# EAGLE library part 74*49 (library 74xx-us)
BCD to seven segment DECODER/DRIVER, open collector

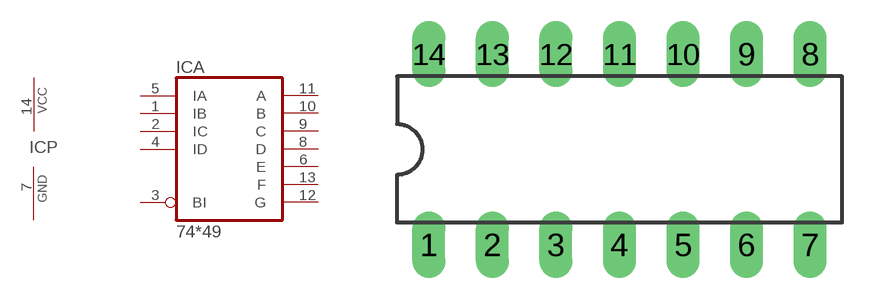
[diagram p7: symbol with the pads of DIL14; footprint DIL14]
Designator prefix IC; gates A=7449 P=PWRN

## 74LS49N  [DIL14]
1  A:IB  in
2  A:IC  in
3  A:BI  in
4  A:ID  in
5  A:IA  in
6  A:E  oc
7  P:GND  pwr
8  A:D  oc
9  A:C  oc
10  A:B  oc
11  A:A  oc
12  A:G  oc
13  A:F  oc
14  P:VCC  pwr

## Footprint DIL14 (pad centres in mm)
Dual In Line Package
drill 0.813 long: 1 -7.62,-3.81; 2 -5.08,-3.81; 3 -2.54,-3.81; 4 0,-3.81; 5 2.54,-3.81; 6 5.08,-3.81; 7 7.62,-3.81; 8 7.62,3.81; 9 5.08,3.81; 10 2.54,3.81; 11 0,3.81; 12 -2.54,3.81; 13 -5.08,3.81; 14 -7.62,3.81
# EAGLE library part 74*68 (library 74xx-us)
Dual 4-bit decade or binary COUNTER

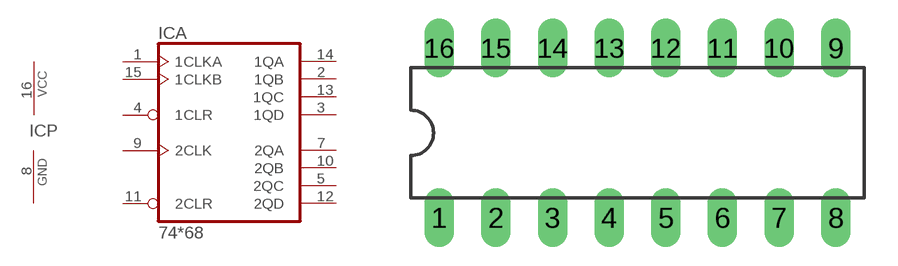
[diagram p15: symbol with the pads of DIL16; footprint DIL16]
Designator prefix IC; gates A=7468 P=PWRN

## 74LS68N  [DIL16]
1  A:1CLKA  in
2  A:1QB  out
3  A:1QD  out
4  A:1CLR  in
5  A:2QC  out
7  A:2QA  out
8  P:GND  pwr
9  A:2CLK  in
10  A:2QB  out
11  A:2CLR  in
12  A:2QD  out
13  A:1QC  out
14  A:1QA  out
15  A:1CLKB  in
16  P:VCC  pwr

## Footprint DIL16 (pad centres in mm)
Dual In Line Package
drill 0.813 long: 1 -8.89,-3.81; 2 -6.35,-3.81; 3 -3.81,-3.81; 4 -1.27,-3.81; 5 1.27,-3.81; 6 3.81,-3.81; 7 6.35,-3.81; 8 8.89,-3.81; 9 8.89,3.81; 10 6.35,3.81; 11 3.81,3.81; 12 1.27,3.81; 13 -1.27,3.81; 14 -3.81,3.81; 15 -6.35,3.81; 16 -8.89,3.81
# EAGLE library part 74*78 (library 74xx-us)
Dual J-K FLIP FLOP, preset, common clock and common clear

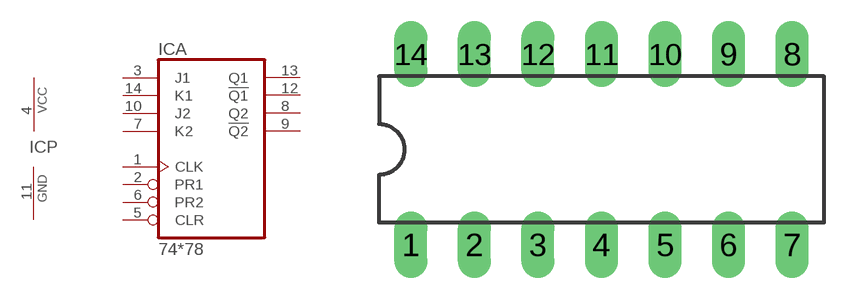
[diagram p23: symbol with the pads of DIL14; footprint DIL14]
Designator prefix IC; gates A=7478 P=PWRN

## 74LS78N  [DIL14]
1  A:CLK  in
2  A:PR1  in
3  A:J1  in
4  P:VCC  pwr
5  A:CLR  in
6  A:PR2  in
7  A:K2  in
8  A:Q2  out
9  A:!Q2  out
10  A:J2  in
11  P:GND  pwr
12  A:!Q1  out
13  A:Q1  out
14  A:K1  in

## Footprint DIL14 (pad centres in mm)
Dual In Line Package
drill 0.813 long: 1 -7.62,-3.81; 2 -5.08,-3.81; 3 -2.54,-3.81; 4 0,-3.81; 5 2.54,-3.81; 6 5.08,-3.81; 7 7.62,-3.81; 8 7.62,3.81; 9 5.08,3.81; 10 2.54,3.81; 11 0,3.81; 12 -2.54,3.81; 13 -5.08,3.81; 14 -7.62,3.81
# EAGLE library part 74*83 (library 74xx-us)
4-bit binary full ADDER, fast carry

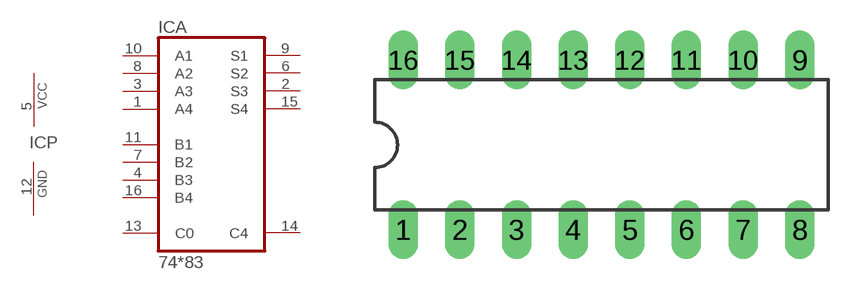
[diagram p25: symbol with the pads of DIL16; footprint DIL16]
Designator prefix IC; gates A=7483 P=PWRN

## 7483N, 74LS83N  [DIL16]
1  A:A4  in
2  A:S3  out
3  A:A3  in
4  A:B3  in
5  P:VCC  pwr
6  A:S2  out
7  A:B2  in
8  A:A2  in
9  A:S1  out
10  A:A1  in
11  A:B1  in
12  P:GND  pwr
13  A:C0  in
14  A:C4  out
15  A:S4  out
16  A:B4  in

## Footprint DIL16 (pad centres in mm)
Dual In Line Package
drill 0.813 long: 1 -8.89,-3.81; 2 -6.35,-3.81; 3 -3.81,-3.81; 4 -1.27,-3.81; 5 1.27,-3.81; 6 3.81,-3.81; 7 6.35,-3.81; 8 8.89,-3.81; 9 8.89,3.81; 10 6.35,3.81; 11 3.81,3.81; 12 1.27,3.81; 13 -1.27,3.81; 14 -3.81,3.81; 15 -6.35,3.81; 16 -8.89,3.81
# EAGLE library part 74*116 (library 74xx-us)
Dual 4-bit LATCH with clear

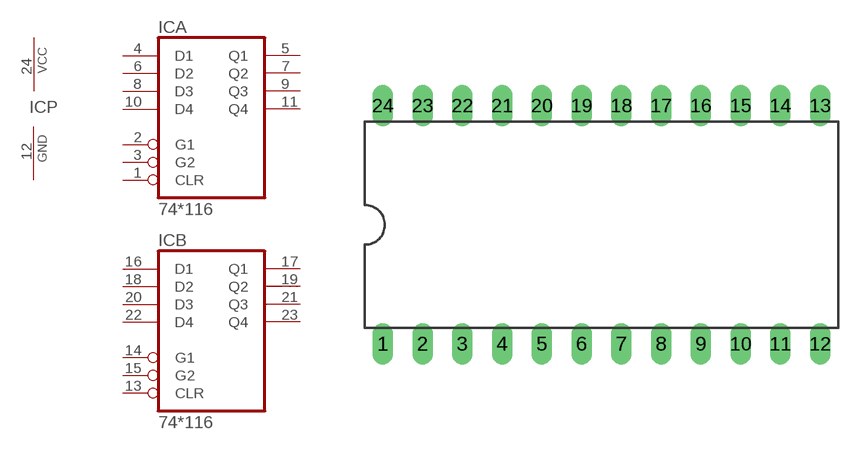
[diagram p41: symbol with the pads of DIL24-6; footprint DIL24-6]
Designator prefix IC; gates A=74116 B=74116 P=PWRN

## 74116N  [DIL24-6]
1  A:CLR  in
2  A:G1  in
3  A:G2  in
4  A:D1  in
5  A:Q1  out
6  A:D2  in
7  A:Q2  out
8  A:D3  in
9  A:Q3  out
10  A:D4  in
11  A:Q4  out
12  P:GND  pwr
13  B:CLR  in
14  B:G1  in
15  B:G2  in
16  B:D1  in
17  B:Q1  out
18  B:D2  in
19  B:Q2  out
20  B:D3  in
21  B:Q3  out
22  B:D4  in
23  B:Q4  out
24  P:VCC  pwr

## Footprint DIL24-6 (pad centres in mm)
Dual In Line Package 0.6 inch
drill 0.813 long: 1 -13.97,-7.62; 2 -11.43,-7.62; 3 -8.89,-7.62; 4 -6.35,-7.62; 5 -3.81,-7.62; 6 -1.27,-7.62; 7 1.27,-7.62; 8 3.81,-7.62; 9 6.35,-7.62; 10 8.89,-7.62; 11 11.43,-7.62; 12 13.97,-7.62; 13 13.97,7.62; 14 11.43,7.62; 15 8.89,7.62; 16 6.35,7.62; 17 3.81,7.62; 18 1.27,7.62; 19 -1.27,7.62; 20 -3.81,7.62; 21 -6.35,7.62; 22 -8.89,7.62; 23 -11.43,7.62; 24 -13.97,7.62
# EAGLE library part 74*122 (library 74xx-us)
Retriggerable monostable MULTIVIBRATOR

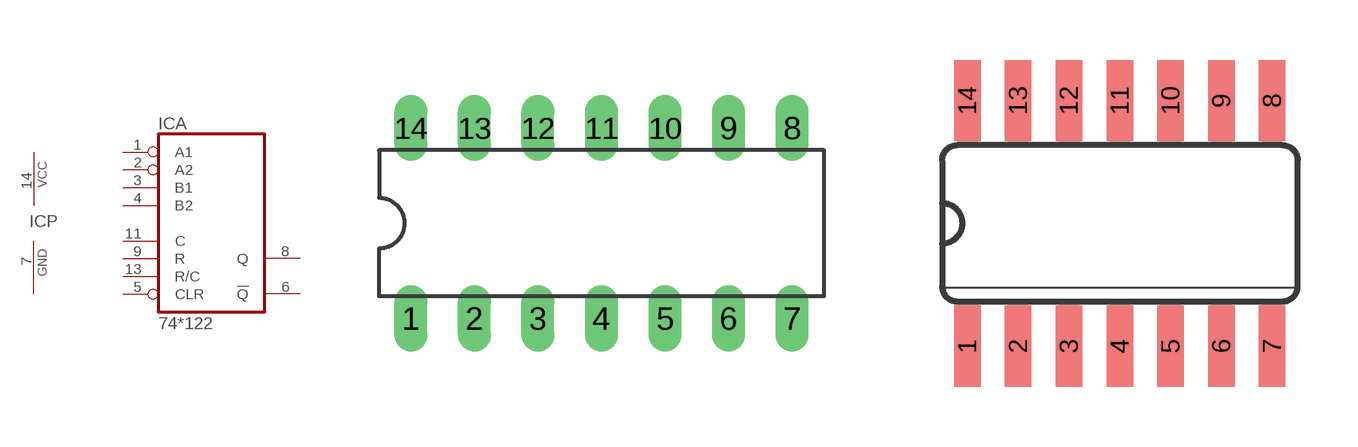
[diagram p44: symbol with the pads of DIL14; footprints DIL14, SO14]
Designator prefix IC; gates A=74122 P=PWRN

## 74LS122N  [DIL14]
1  A:A1  in
2  A:A2  in
3  A:B1  in
4  A:B2  in
5  A:CLR  in
6  A:!Q  out
7  P:GND  pwr
8  A:Q  out
9  A:R  in
11  A:C  in
13  A:R/C  in
14  P:VCC  pwr

## 74LS122D  [SO14]
Pads as for DIL14

## Footprint DIL14 (pad centres in mm)
Dual In Line Package
drill 0.813 long: 1 -7.62,-3.81; 2 -5.08,-3.81; 3 -2.54,-3.81; 4 0,-3.81; 5 2.54,-3.81; 6 5.08,-3.81; 7 7.62,-3.81; 8 7.62,3.81; 9 5.08,3.81; 10 2.54,3.81; 11 0,3.81; 12 -2.54,3.81; 13 -5.08,3.81; 14 -7.62,3.81

## Footprint SO14 (pad centres in mm)
Small Outline package 150 mil
smd 0.66 x 2.032: 1 -3.81,-3.073; 2 -2.54,-3.073; 3 -1.27,-3.073; 4 0,-3.073; 5 1.27,-3.073; 6 2.54,-3.073; 7 3.81,-3.073; 8 3.81,3.073; 9 2.54,3.073; 10 1.27,3.073; 11 0,3.073; 12 -1.27,3.073; 13 -2.54,3.073; 14 -3.81,3.073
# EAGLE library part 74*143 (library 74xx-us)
4-bit COUNTER/LATCH SEVEN-SEGMENT LED/LAMP DRIVER

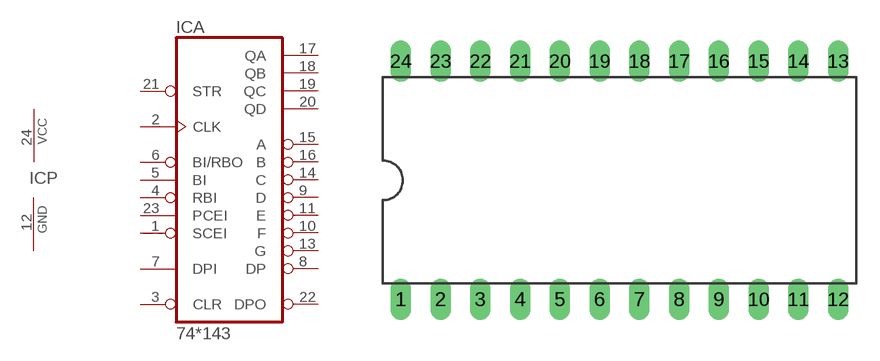
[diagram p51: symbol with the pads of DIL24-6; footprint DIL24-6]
Designator prefix IC; gates A=74143 P=PWRN

## 74143N  [DIL24-6]
1  A:SCEI  in
2  A:CLK  in
3  A:CLR  in
4  A:RBI  in
5  A:BI  in
6  A:BI/RBO
7  A:DPI  in
8  A:DP  oc
9  A:D  oc
10  A:F  oc
11  A:E  oc
12  P:GND  pwr
13  A:G  oc
14  A:C  oc
15  A:A  oc
16  A:B  oc
17  A:QA  out
18  A:QB  out
19  A:QC  out
20  A:QD  out
21  A:STR  in
22  A:DPO  out
23  A:PCEI  in
24  P:VCC  pwr

## Footprint DIL24-6 (pad centres in mm)
Dual In Line Package 0.6 inch
drill 0.813 long: 1 -13.97,-7.62; 2 -11.43,-7.62; 3 -8.89,-7.62; 4 -6.35,-7.62; 5 -3.81,-7.62; 6 -1.27,-7.62; 7 1.27,-7.62; 8 3.81,-7.62; 9 6.35,-7.62; 10 8.89,-7.62; 11 11.43,-7.62; 12 13.97,-7.62; 13 13.97,7.62; 14 11.43,7.62; 15 8.89,7.62; 16 6.35,7.62; 17 3.81,7.62; 18 1.27,7.62; 19 -1.27,7.62; 20 -3.81,7.62; 21 -6.35,7.62; 22 -8.89,7.62; 23 -11.43,7.62; 24 -13.97,7.62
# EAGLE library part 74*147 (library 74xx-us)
10-line to 4-line and 8-line to 3-line PRIORITY DECODER

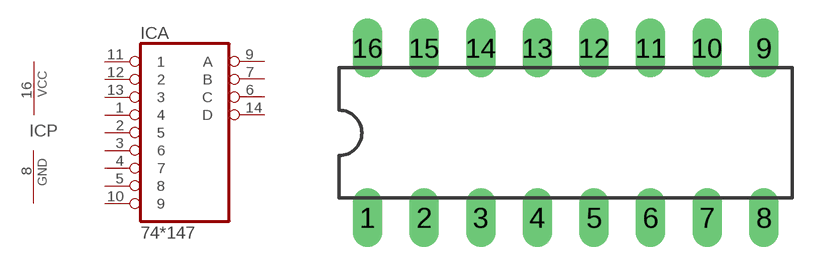
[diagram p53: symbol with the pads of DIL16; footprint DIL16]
Designator prefix IC; gates A=74147 P=PWRN

## 74147N  [DIL16]
1  A:4  in
2  A:5  in
3  A:6  in
4  A:7  in
5  A:8  in
6  A:C  out
7  A:B  out
8  P:GND  pwr
9  A:A  out
10  A:9  in
11  A:1  in
12  A:2  in
13  A:3  in
14  A:D  out
16  P:VCC  pwr

## Footprint DIL16 (pad centres in mm)
Dual In Line Package
drill 0.813 long: 1 -8.89,-3.81; 2 -6.35,-3.81; 3 -3.81,-3.81; 4 -1.27,-3.81; 5 1.27,-3.81; 6 3.81,-3.81; 7 6.35,-3.81; 8 8.89,-3.81; 9 8.89,3.81; 10 6.35,3.81; 11 3.81,3.81; 12 1.27,3.81; 13 -1.27,3.81; 14 -3.81,3.81; 15 -6.35,3.81; 16 -8.89,3.81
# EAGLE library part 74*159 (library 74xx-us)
4-line to 16-line DECODER/DEMULTIPLEXER, open collector

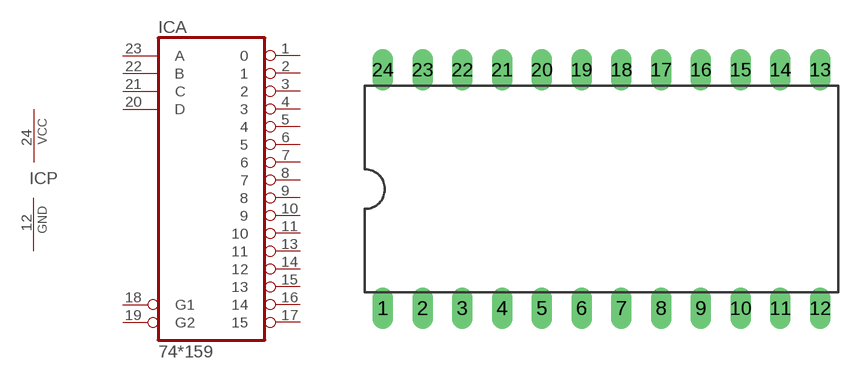
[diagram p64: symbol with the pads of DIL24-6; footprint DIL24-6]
Designator prefix IC; gates A=74159 P=PWRN

## 74159N  [DIL24-6]
1  A:0  oc
2  A:1  oc
3  A:2  oc
4  A:3  oc
5  A:4  oc
6  A:5  oc
7  A:6  oc
8  A:7  oc
9  A:8  oc
10  A:9  oc
11  A:10  oc
12  P:GND  pwr
13  A:11  oc
14  A:12  oc
15  A:13  oc
16  A:14  oc
17  A:15  oc
18  A:G1  in
19  A:G2  in
20  A:D  in
21  A:C  in
22  A:B  in
23  A:A  in
24  P:VCC  pwr

## Footprint DIL24-6 (pad centres in mm)
Dual In Line Package 0.6 inch
drill 0.813 long: 1 -13.97,-7.62; 2 -11.43,-7.62; 3 -8.89,-7.62; 4 -6.35,-7.62; 5 -3.81,-7.62; 6 -1.27,-7.62; 7 1.27,-7.62; 8 3.81,-7.62; 9 6.35,-7.62; 10 8.89,-7.62; 11 11.43,-7.62; 12 13.97,-7.62; 13 13.97,7.62; 14 11.43,7.62; 15 8.89,7.62; 16 6.35,7.62; 17 3.81,7.62; 18 1.27,7.62; 19 -1.27,7.62; 20 -3.81,7.62; 21 -6.35,7.62; 22 -8.89,7.62; 23 -11.43,7.62; 24 -13.97,7.62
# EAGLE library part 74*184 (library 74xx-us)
BCD to binary and binary to BCD CONVERTER

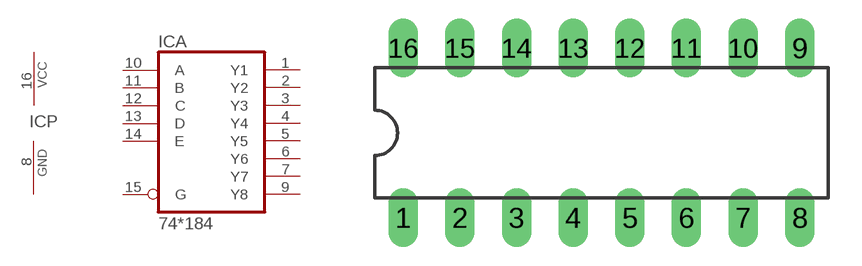
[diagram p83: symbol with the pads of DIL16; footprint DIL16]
Designator prefix IC; gates A=74184 P=PWRN

## 74184N  [DIL16]
1  A:Y1  out
2  A:Y2  out
3  A:Y3  out
4  A:Y4  out
5  A:Y5  out
6  A:Y6  out
7  A:Y7  out
8  P:GND  pwr
9  A:Y8  out
10  A:A  in
11  A:B  in
12  A:C  in
13  A:D  in
14  A:E  in
15  A:G  in
16  P:VCC  pwr

## Footprint DIL16 (pad centres in mm)
Dual In Line Package
drill 0.813 long: 1 -8.89,-3.81; 2 -6.35,-3.81; 3 -3.81,-3.81; 4 -1.27,-3.81; 5 1.27,-3.81; 6 3.81,-3.81; 7 6.35,-3.81; 8 8.89,-3.81; 9 8.89,3.81; 10 6.35,3.81; 11 3.81,3.81; 12 1.27,3.81; 13 -1.27,3.81; 14 -3.81,3.81; 15 -6.35,3.81; 16 -8.89,3.81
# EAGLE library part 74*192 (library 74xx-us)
Synchronous 4-bit UP/DOWN COUNTER

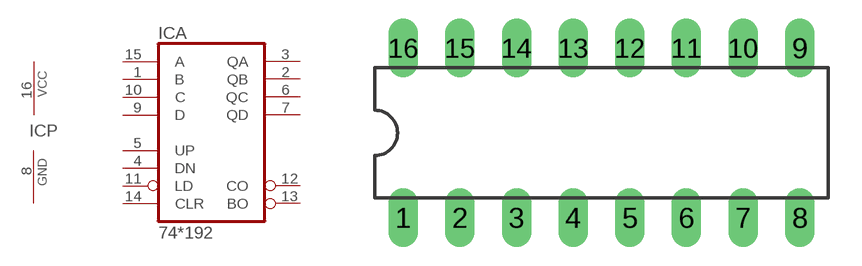
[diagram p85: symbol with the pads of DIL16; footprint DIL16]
Designator prefix IC; gates A=74192 P=PWRN

## 74192N, 74LS192N  [DIL16]
1  A:B  in
2  A:QB  out
3  A:QA  out
4  A:DN  in
5  A:UP  in
6  A:QC  out
7  A:QD  out
8  P:GND  pwr
9  A:D  in
10  A:C  in
11  A:LD  in
12  A:CO  out
13  A:BO  out
14  A:CLR  in
15  A:A  in
16  P:VCC  pwr

## Footprint DIL16 (pad centres in mm)
Dual In Line Package
drill 0.813 long: 1 -8.89,-3.81; 2 -6.35,-3.81; 3 -3.81,-3.81; 4 -1.27,-3.81; 5 1.27,-3.81; 6 3.81,-3.81; 7 6.35,-3.81; 8 8.89,-3.81; 9 8.89,3.81; 10 6.35,3.81; 11 3.81,3.81; 12 1.27,3.81; 13 -1.27,3.81; 14 -3.81,3.81; 15 -6.35,3.81; 16 -8.89,3.81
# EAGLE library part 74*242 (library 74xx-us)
Quadruple BUS TRANSCEIVER

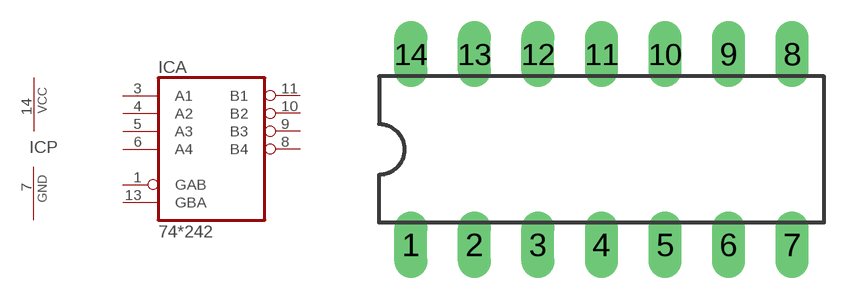
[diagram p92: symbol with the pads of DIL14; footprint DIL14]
Designator prefix IC; gates A=74242 P=PWRN

## 74242N  [DIL14]
1  A:GAB  in
3  A:A1
4  A:A2
5  A:A3
6  A:A4
7  P:GND  pwr
8  A:B4
9  A:B3
10  A:B2
11  A:B1
13  A:GBA  in
14  P:VCC  pwr

## Footprint DIL14 (pad centres in mm)
Dual In Line Package
drill 0.813 long: 1 -7.62,-3.81; 2 -5.08,-3.81; 3 -2.54,-3.81; 4 0,-3.81; 5 2.54,-3.81; 6 5.08,-3.81; 7 7.62,-3.81; 8 7.62,3.81; 9 5.08,3.81; 10 2.54,3.81; 11 0,3.81; 12 -2.54,3.81; 13 -5.08,3.81; 14 -7.62,3.81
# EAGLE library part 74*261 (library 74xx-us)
2 by 4 bit parallel binary MULTIPLEXER

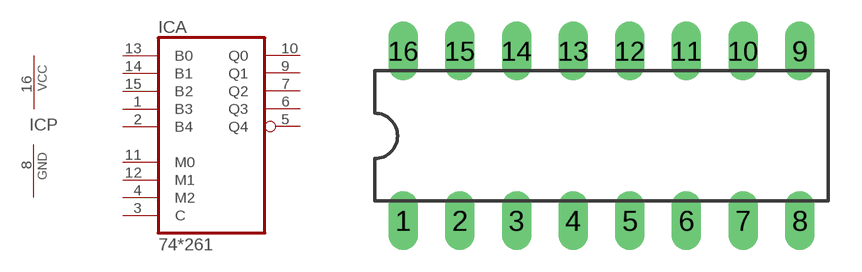
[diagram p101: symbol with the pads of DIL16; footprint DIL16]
Designator prefix IC; gates A=74261 P=PWRN

## 74261N  [DIL16]
1  A:B3  in
2  A:B4  in
3  A:C  in
4  A:M2  in
5  A:Q4  out
6  A:Q3  out
7  A:Q2  out
8  P:GND  pwr
9  A:Q1  out
10  A:Q0  out
11  A:M0  in
12  A:M1  in
13  A:B0  in
14  A:B1  in
15  A:B2  in
16  P:VCC  pwr

## Footprint DIL16 (pad centres in mm)
Dual In Line Package
drill 0.813 long: 1 -8.89,-3.81; 2 -6.35,-3.81; 3 -3.81,-3.81; 4 -1.27,-3.81; 5 1.27,-3.81; 6 3.81,-3.81; 7 6.35,-3.81; 8 8.89,-3.81; 9 8.89,3.81; 10 6.35,3.81; 11 3.81,3.81; 12 1.27,3.81; 13 -1.27,3.81; 14 -3.81,3.81; 15 -6.35,3.81; 16 -8.89,3.81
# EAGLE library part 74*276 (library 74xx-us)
Quadruple J-K FLIP FLOP

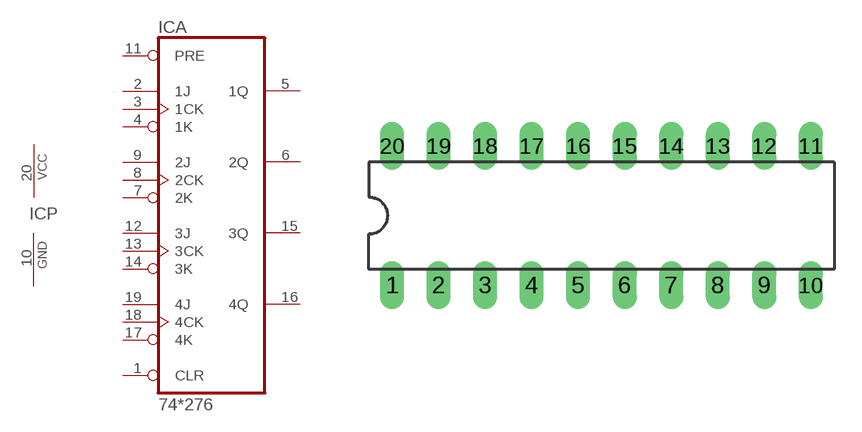
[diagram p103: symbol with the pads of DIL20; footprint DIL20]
Designator prefix IC; gates A=74276 P=PWRN

## 74276N  [DIL20]
1  A:CLR  in
2  A:1J  in
3  A:1CK  in
4  A:1K  in
5  A:1Q  out
6  A:2Q  out
7  A:2K  in
8  A:2CK  in
9  A:2J  in
10  P:GND  pwr
11  A:PRE  in
12  A:3J  in
13  A:3CK  in
14  A:3K  in
15  A:3Q  out
16  A:4Q  out
17  A:4K  in
18  A:4CK  in
19  A:4J  in
20  P:VCC  pwr

## Footprint DIL20 (pad centres in mm)
Dual In Line Package
drill 0.813 long: 1 -11.43,-3.81; 2 -8.89,-3.81; 3 -6.35,-3.81; 4 -3.81,-3.81; 5 -1.27,-3.81; 6 1.27,-3.81; 7 3.81,-3.81; 8 6.35,-3.81; 9 8.89,-3.81; 10 11.43,-3.81; 11 11.43,3.81; 12 8.89,3.81; 13 6.35,3.81; 14 3.81,3.81; 15 1.27,3.81; 16 -1.27,3.81; 17 -3.81,3.81; 18 -6.35,3.81; 19 -8.89,3.81; 20 -11.43,3.81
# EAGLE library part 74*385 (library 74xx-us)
Quadruple serial ADDER/SUBTRACTOR

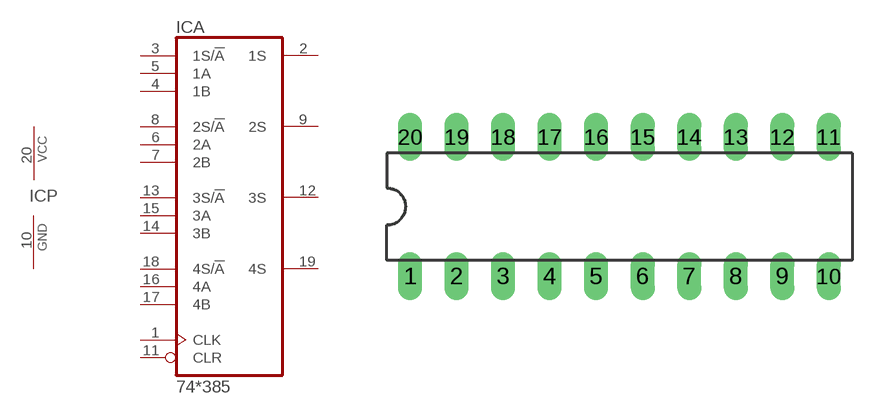
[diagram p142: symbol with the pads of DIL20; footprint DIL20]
Designator prefix IC; gates A=74385 P=PWRN

## 74385N  [DIL20]
1  A:CLK  in
2  A:1S  out
3  A:1S/!A  in
4  A:1B  in
5  A:1A  in
6  A:2A  in
7  A:2B  in
8  A:2S/!A  in
9  A:2S  out
10  P:GND  pwr
11  A:CLR  in
12  A:3S  out
13  A:3S/!A  in
14  A:3B  in
15  A:3A  in
16  A:4A  in
17  A:4B  in
18  A:4S/!A  in
19  A:4S  out
20  P:VCC  pwr

## Footprint DIL20 (pad centres in mm)
Dual In Line Package
drill 0.813 long: 1 -11.43,-3.81; 2 -8.89,-3.81; 3 -6.35,-3.81; 4 -3.81,-3.81; 5 -1.27,-3.81; 6 1.27,-3.81; 7 3.81,-3.81; 8 6.35,-3.81; 9 8.89,-3.81; 10 11.43,-3.81; 11 11.43,3.81; 12 8.89,3.81; 13 6.35,3.81; 14 3.81,3.81; 15 1.27,3.81; 16 -1.27,3.81; 17 -3.81,3.81; 18 -6.35,3.81; 19 -8.89,3.81; 20 -11.43,3.81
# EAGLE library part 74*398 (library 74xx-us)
Quadruple 2-input MULTIPLEXER, storage

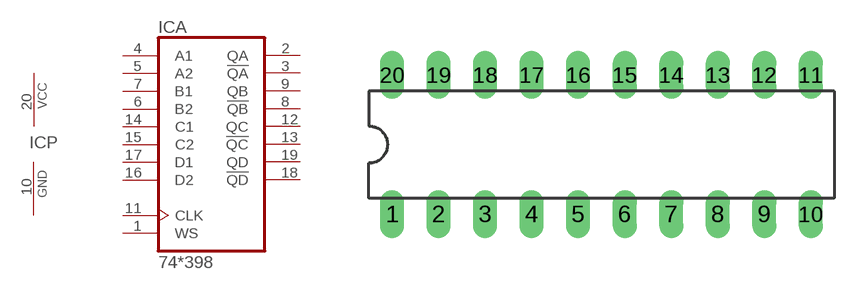
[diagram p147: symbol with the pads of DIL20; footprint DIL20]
Designator prefix IC; gates A=74398 P=PWRN

## 74398N  [DIL20]
1  A:WS  in
2  A:QA  out
3  A:!QA  out
4  A:A1  in
5  A:A2  in
6  A:B2  in
7  A:B1  in
8  A:!QB  out
9  A:QB  out
10  P:GND  pwr
11  A:CLK  in
12  A:QC  out
13  A:!QC  out
14  A:C1  in
15  A:C2  in
16  A:D2  in
17  A:D1  in
18  A:!QD  out
19  A:QD  out
20  P:VCC  pwr

## Footprint DIL20 (pad centres in mm)
Dual In Line Package
drill 0.813 long: 1 -11.43,-3.81; 2 -8.89,-3.81; 3 -6.35,-3.81; 4 -3.81,-3.81; 5 -1.27,-3.81; 6 1.27,-3.81; 7 3.81,-3.81; 8 6.35,-3.81; 9 8.89,-3.81; 10 11.43,-3.81; 11 11.43,3.81; 12 8.89,3.81; 13 6.35,3.81; 14 3.81,3.81; 15 1.27,3.81; 16 -1.27,3.81; 17 -3.81,3.81; 18 -6.35,3.81; 19 -8.89,3.81; 20 -11.43,3.81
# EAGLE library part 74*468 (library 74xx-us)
Inverted octal BUFFER, 3-state

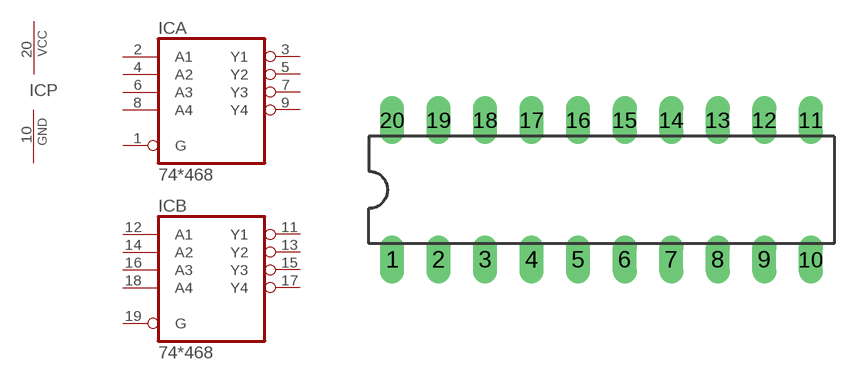
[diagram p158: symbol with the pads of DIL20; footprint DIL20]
Designator prefix IC; gates A=74468 B=74468 P=PWRN

## 74468N  [DIL20]
1  A:G  in
2  A:A1  in
3  A:Y1  hiz
4  A:A2  in
5  A:Y2  hiz
6  A:A3  in
7  A:Y3  hiz
8  A:A4  in
9  A:Y4  hiz
10  P:GND  pwr
11  B:Y1  hiz
12  B:A1  in
13  B:Y2  hiz
14  B:A2  in
15  B:Y3  hiz
16  B:A3  in
17  B:Y4  hiz
18  B:A4  in
19  B:G  in
20  P:VCC  pwr

## Footprint DIL20 (pad centres in mm)
Dual In Line Package
drill 0.813 long: 1 -11.43,-3.81; 2 -8.89,-3.81; 3 -6.35,-3.81; 4 -3.81,-3.81; 5 -1.27,-3.81; 6 1.27,-3.81; 7 3.81,-3.81; 8 6.35,-3.81; 9 8.89,-3.81; 10 11.43,-3.81; 11 11.43,3.81; 12 8.89,3.81; 13 6.35,3.81; 14 3.81,3.81; 15 1.27,3.81; 16 -1.27,3.81; 17 -3.81,3.81; 18 -6.35,3.81; 19 -8.89,3.81; 20 -11.43,3.81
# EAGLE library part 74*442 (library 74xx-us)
4 bit tridirectional BUS DRIVER

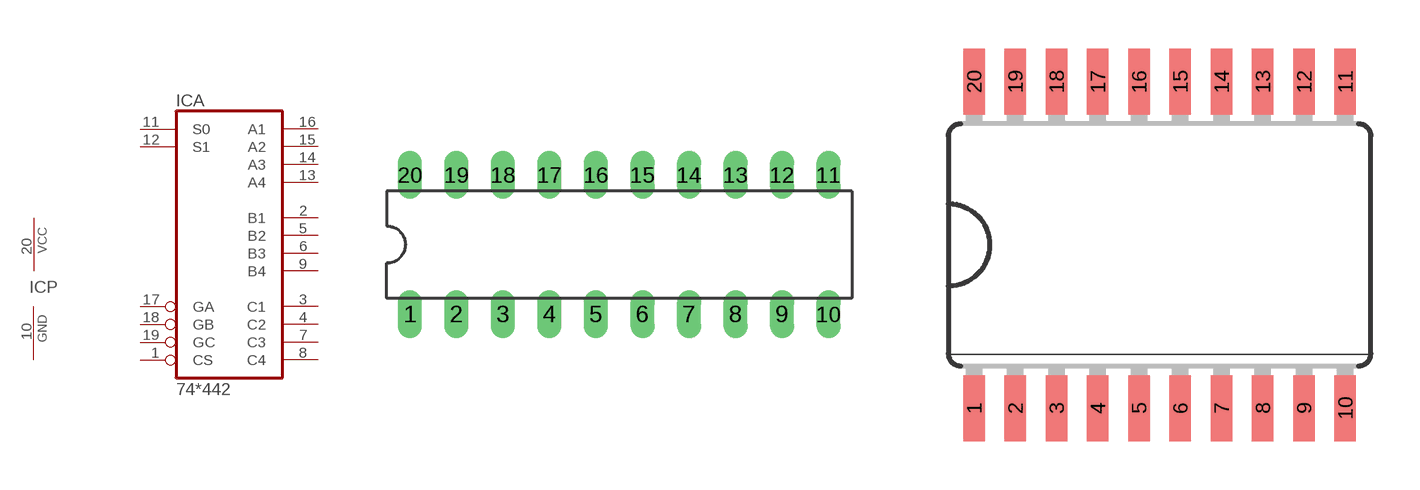
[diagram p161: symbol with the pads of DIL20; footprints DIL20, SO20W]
Designator prefix IC; gates A=74440 P=PWRN

## 74LS442N  [DIL20]
1  A:CS  in
2  A:B1
3  A:C1
4  A:C2
5  A:B2
6  A:B3
7  A:C3
8  A:C4
9  A:B4
10  P:GND  pwr
11  A:S0  in
12  A:S1  in
13  A:A4
14  A:A3
15  A:A2
16  A:A1
17  A:GA  in
18  A:GB  in
19  A:GC  in
20  P:VCC  pwr

## 74LS442J  [SO20W]
Pads as for DIL20

## Footprint DIL20 (pad centres in mm)
Dual In Line Package
drill 0.813 long: 1 -11.43,-3.81; 2 -8.89,-3.81; 3 -6.35,-3.81; 4 -3.81,-3.81; 5 -1.27,-3.81; 6 1.27,-3.81; 7 3.81,-3.81; 8 6.35,-3.81; 9 8.89,-3.81; 10 11.43,-3.81; 11 11.43,3.81; 12 8.89,3.81; 13 6.35,3.81; 14 3.81,3.81; 15 1.27,3.81; 16 -1.27,3.81; 17 -3.81,3.81; 18 -6.35,3.81; 19 -8.89,3.81; 20 -11.43,3.81

## Footprint SO20W (pad centres in mm)
Wide Small Outline package 300 mil
smd 0.66 x 2.032: 1 -5.715,-5.029; 2 -4.445,-5.029; 3 -3.175,-5.029; 4 -1.905,-5.029; 5 -0.635,-5.029; 6 0.635,-5.029; 7 1.905,-5.029; 8 3.175,-5.029; 9 4.445,-5.029; 10 5.715,-5.029; 11 5.715,5.029; 12 4.445,5.029; 13 3.175,5.029; 14 1.905,5.029; 15 0.635,5.029; 16 -0.635,5.029; 17 -1.905,5.029; 18 -3.175,5.029; 19 -4.445,5.029; 20 -5.715,5.029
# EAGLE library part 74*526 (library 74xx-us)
16-bit programmable COMPARATOR

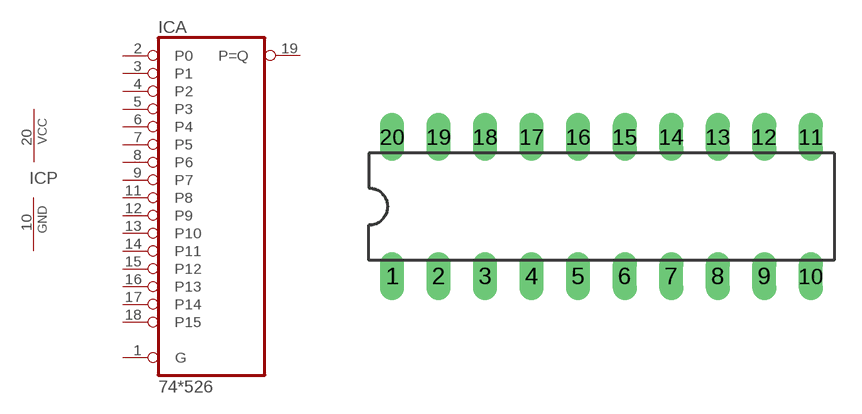
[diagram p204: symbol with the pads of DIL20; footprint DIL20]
Designator prefix IC; gates A=74526 P=PWRN

## 74ALS526N  [DIL20]
1  A:G  in
2  A:P0  in
3  A:P1  in
4  A:P2  in
5  A:P3  in
6  A:P4  in
7  A:P5  in
8  A:P6  in
9  A:P7  in
10  P:GND  pwr
11  A:P8  in
12  A:P9  in
13  A:P10  in
14  A:P11  in
15  A:P12  in
16  A:P13  in
17  A:P14  in
18  A:P15  in
19  A:P=Q  out
20  P:VCC  pwr

## Footprint DIL20 (pad centres in mm)
Dual In Line Package
drill 0.813 long: 1 -11.43,-3.81; 2 -8.89,-3.81; 3 -6.35,-3.81; 4 -3.81,-3.81; 5 -1.27,-3.81; 6 1.27,-3.81; 7 3.81,-3.81; 8 6.35,-3.81; 9 8.89,-3.81; 10 11.43,-3.81; 11 11.43,3.81; 12 8.89,3.81; 13 6.35,3.81; 14 3.81,3.81; 15 1.27,3.81; 16 -1.27,3.81; 17 -3.81,3.81; 18 -6.35,3.81; 19 -8.89,3.81; 20 -11.43,3.81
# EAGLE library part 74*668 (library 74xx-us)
4-bit synchronous decade COUNTER, preset

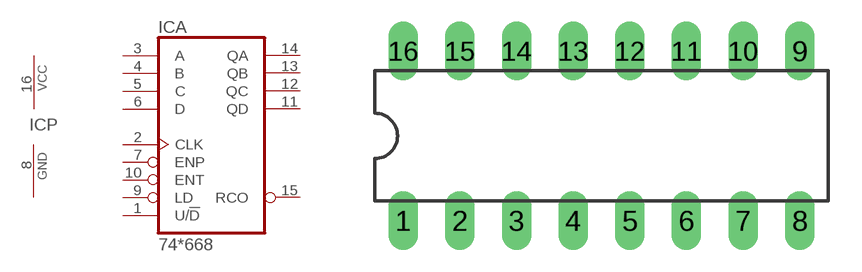
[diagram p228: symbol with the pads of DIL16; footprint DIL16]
Designator prefix IC; gates A=74668 P=PWRN

## 74668N  [DIL16]
1  A:U/!D  in
2  A:CLK  in
3  A:A  in
4  A:B  in
5  A:C  in
6  A:D  in
7  A:ENP  in
8  P:GND  pwr
9  A:LD  in
10  A:ENT  in
11  A:QD  out
12  A:QC  out
13  A:QB  out
14  A:QA  out
15  A:RCO  out
16  P:VCC  pwr

## Footprint DIL16 (pad centres in mm)
Dual In Line Package
drill 0.813 long: 1 -8.89,-3.81; 2 -6.35,-3.81; 3 -3.81,-3.81; 4 -1.27,-3.81; 5 1.27,-3.81; 6 3.81,-3.81; 7 6.35,-3.81; 8 8.89,-3.81; 9 8.89,3.81; 10 6.35,3.81; 11 3.81,3.81; 12 1.27,3.81; 13 -1.27,3.81; 14 -3.81,3.81; 15 -6.35,3.81; 16 -8.89,3.81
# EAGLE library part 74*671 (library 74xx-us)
4-bit universal SHIFT REGISTER/LATCH, 3-state

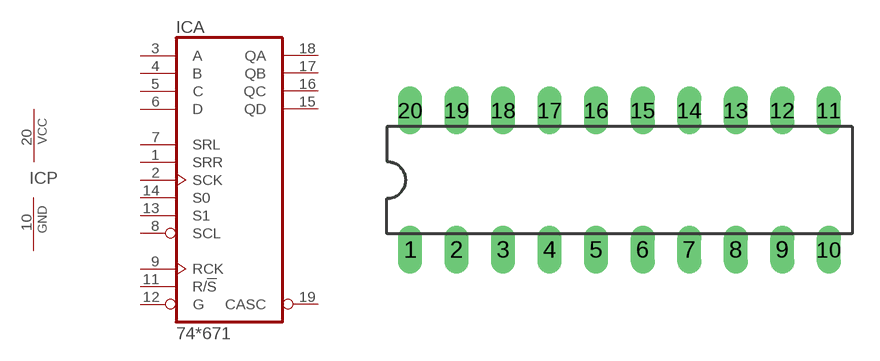
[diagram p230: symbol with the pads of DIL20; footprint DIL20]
Designator prefix IC; gates A=74671 P=PWRN

## 74671N  [DIL20]
1  A:SRR  in
2  A:SCK  in
3  A:A  in
4  A:B  in
5  A:C  in
6  A:D  in
7  A:SRL  in
8  A:SCL  in
9  A:RCK  in
10  P:GND  pwr
11  A:R/!S  in
12  A:G  in
13  A:S1  in
14  A:S0  in
15  A:QD  hiz
16  A:QC  hiz
17  A:QB  hiz
18  A:QA  hiz
19  A:CASC  out
20  P:VCC  pwr

## Footprint DIL20 (pad centres in mm)
Dual In Line Package
drill 0.813 long: 1 -11.43,-3.81; 2 -8.89,-3.81; 3 -6.35,-3.81; 4 -3.81,-3.81; 5 -1.27,-3.81; 6 1.27,-3.81; 7 3.81,-3.81; 8 6.35,-3.81; 9 8.89,-3.81; 10 11.43,-3.81; 11 11.43,3.81; 12 8.89,3.81; 13 6.35,3.81; 14 3.81,3.81; 15 1.27,3.81; 16 -1.27,3.81; 17 -3.81,3.81; 18 -6.35,3.81; 19 -8.89,3.81; 20 -11.43,3.81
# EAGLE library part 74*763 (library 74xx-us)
8-bit inverting BUS DRIVER

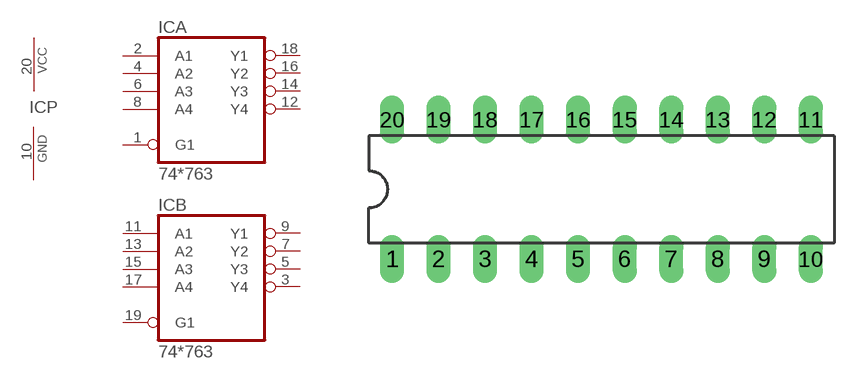
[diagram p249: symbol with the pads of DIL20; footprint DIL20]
Designator prefix IC; gates A=74763 B=74763 P=PWRN

## 74AS763N  [DIL20]
1  A:G1  in
2  A:A1  in
3  B:Y4  oc
4  A:A2  in
5  B:Y3  oc
6  A:A3  in
7  B:Y2  oc
8  A:A4  in
9  B:Y1  oc
10  P:GND  pwr
11  B:A1  in
12  A:Y4  oc
13  B:A2  in
14  A:Y3  oc
15  B:A3  in
16  A:Y2  oc
17  B:A4  in
18  A:Y1  oc
19  B:G1  in
20  P:VCC  pwr

## Footprint DIL20 (pad centres in mm)
Dual In Line Package
drill 0.813 long: 1 -11.43,-3.81; 2 -8.89,-3.81; 3 -6.35,-3.81; 4 -3.81,-3.81; 5 -1.27,-3.81; 6 1.27,-3.81; 7 3.81,-3.81; 8 6.35,-3.81; 9 8.89,-3.81; 10 11.43,-3.81; 11 11.43,3.81; 12 8.89,3.81; 13 6.35,3.81; 14 3.81,3.81; 15 1.27,3.81; 16 -1.27,3.81; 17 -3.81,3.81; 18 -6.35,3.81; 19 -8.89,3.81; 20 -11.43,3.81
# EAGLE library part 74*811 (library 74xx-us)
Quad EX-NOR gate

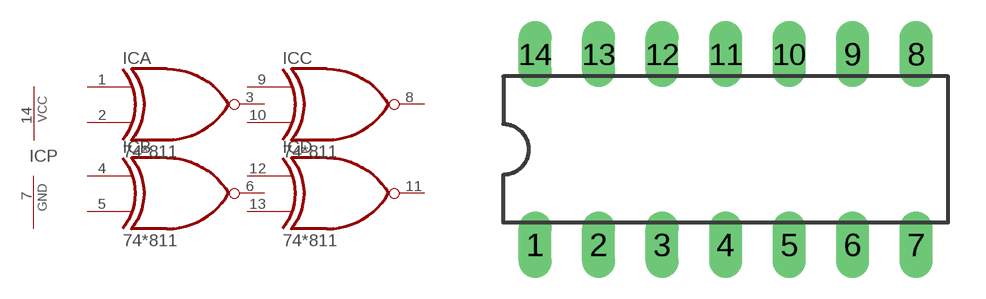
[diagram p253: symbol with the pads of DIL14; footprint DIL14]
Designator prefix IC; gates A=74811 B=74811 C=74811 D=74811 P=PWRN

## 74811N  [DIL14]
1  A:I0  in
2  A:I1  in
3  A:O  oc
4  B:I0  in
5  B:I1  in
6  B:O  oc
7  P:GND  pwr
8  C:O  oc
9  C:I0  in
10  C:I1  in
11  D:O  oc
12  D:I0  in
13  D:I1  in
14  P:VCC  pwr

## Footprint DIL14 (pad centres in mm)
Dual In Line Package
drill 0.813 long: 1 -7.62,-3.81; 2 -5.08,-3.81; 3 -2.54,-3.81; 4 0,-3.81; 5 2.54,-3.81; 6 5.08,-3.81; 7 7.62,-3.81; 8 7.62,3.81; 9 5.08,3.81; 10 2.54,3.81; 11 0,3.81; 12 -2.54,3.81; 13 -5.08,3.81; 14 -7.62,3.81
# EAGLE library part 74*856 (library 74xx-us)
8-bit bidirectional DRIVER and PORT CONTROLLER

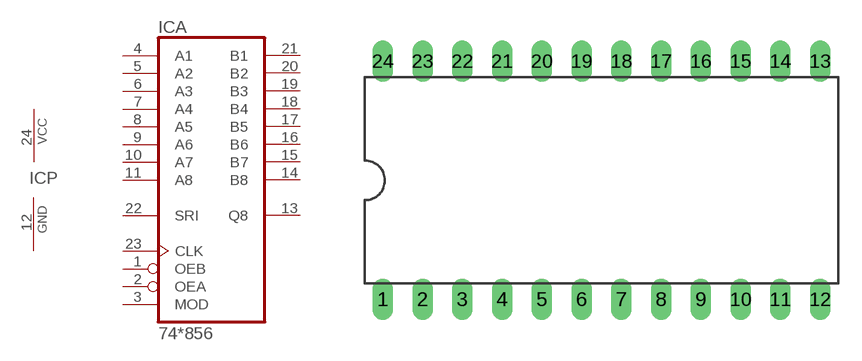
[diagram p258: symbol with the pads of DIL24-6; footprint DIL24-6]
Designator prefix IC; gates A=74856 P=PWRN

## 74AS856NT  [DIL24-6]
1  A:OEB  in
2  A:OEA  in
3  A:MOD  in
4  A:A1
5  A:A2
6  A:A3
7  A:A4
8  A:A5
9  A:A6
10  A:A7
11  A:A8
12  P:GND  pwr
13  A:Q8  hiz
14  A:B8
15  A:B7
16  A:B6
17  A:B5
18  A:B4
19  A:B3
20  A:B2
21  A:B1
22  A:SRI  in
23  A:CLK  in
24  P:VCC  pwr

## Footprint DIL24-6 (pad centres in mm)
Dual In Line Package 0.6 inch
drill 0.813 long: 1 -13.97,-7.62; 2 -11.43,-7.62; 3 -8.89,-7.62; 4 -6.35,-7.62; 5 -3.81,-7.62; 6 -1.27,-7.62; 7 1.27,-7.62; 8 3.81,-7.62; 9 6.35,-7.62; 10 8.89,-7.62; 11 11.43,-7.62; 12 13.97,-7.62; 13 13.97,7.62; 14 11.43,7.62; 15 8.89,7.62; 16 6.35,7.62; 17 3.81,7.62; 18 1.27,7.62; 19 -1.27,7.62; 20 -3.81,7.62; 21 -6.35,7.62; 22 -8.89,7.62; 23 -11.43,7.62; 24 -13.97,7.62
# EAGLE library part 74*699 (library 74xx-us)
Synchronous binary UP/DOWN COUNTER, register, 3-state

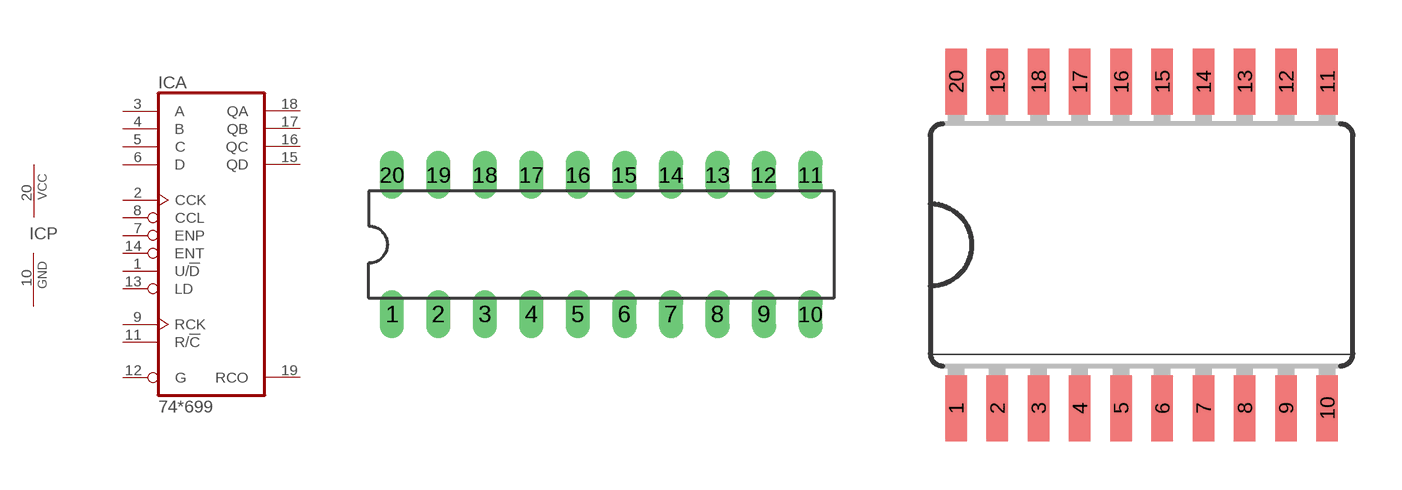
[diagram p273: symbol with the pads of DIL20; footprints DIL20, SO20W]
Designator prefix IC; gates A=74696 P=PWRN

## 74LS699N  [DIL20]
1  A:U/!D  in
2  A:CCK  in
3  A:A  in
4  A:B  in
5  A:C  in
6  A:D  in
7  A:ENP  in
8  A:CCL  in
9  A:RCK  in
10  P:GND  pwr
11  A:R/!C  in
12  A:G  in
13  A:LD  in
14  A:ENT  in
15  A:QD  hiz
16  A:QC  hiz
17  A:QB  hiz
18  A:QA  hiz
19  A:RCO  out
20  P:VCC  pwr

## 74LS699DW  [SO20W]
Pads as for DIL20

## 74LS699FK  [LCC20]
Pads as for DIL20

## Footprint DIL20 (pad centres in mm)
Dual In Line Package
drill 0.813 long: 1 -11.43,-3.81; 2 -8.89,-3.81; 3 -6.35,-3.81; 4 -3.81,-3.81; 5 -1.27,-3.81; 6 1.27,-3.81; 7 3.81,-3.81; 8 6.35,-3.81; 9 8.89,-3.81; 10 11.43,-3.81; 11 11.43,3.81; 12 8.89,3.81; 13 6.35,3.81; 14 3.81,3.81; 15 1.27,3.81; 16 -1.27,3.81; 17 -3.81,3.81; 18 -6.35,3.81; 19 -8.89,3.81; 20 -11.43,3.81

## Footprint SO20W (pad centres in mm)
Wide Small Outline package 300 mil
smd 0.66 x 2.032: 1 -5.715,-5.029; 2 -4.445,-5.029; 3 -3.175,-5.029; 4 -1.905,-5.029; 5 -0.635,-5.029; 6 0.635,-5.029; 7 1.905,-5.029; 8 3.175,-5.029; 9 4.445,-5.029; 10 5.715,-5.029; 11 5.715,5.029; 12 4.445,5.029; 13 3.175,5.029; 14 1.905,5.029; 15 0.635,5.029; 16 -0.635,5.029; 17 -1.905,5.029; 18 -3.175,5.029; 19 -4.445,5.029; 20 -5.715,5.029

## Footprint LCC20 (pad centres in mm)
Leadless Chip Carrier Ceramic Package
smd 0.8 x 3.4: 1 0,3.8
smd 0.8 x 2: 2 -1.27,4.5; 3 -2.54,4.5; 9 -2.54,-4.5; 10 -1.27,-4.5; 11 0,-4.5; 12 1.27,-4.5; 13 2.54,-4.5; 19 2.54,4.5; 20 1.27,4.5
smd 2 x 0.8: 4 -4.5,2.54; 5 -4.5,1.27; 6 -4.5,0; 7 -4.5,-1.27; 8 -4.5,-2.54; 14 4.5,-2.54; 15 4.5,-1.27; 16 4.5,0; 17 4.5,1.27; 18 4.5,2.54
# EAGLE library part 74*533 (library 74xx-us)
Inverting 8-bit D type LATCH

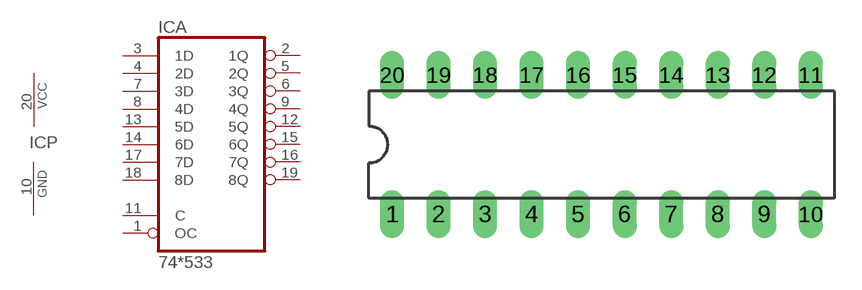
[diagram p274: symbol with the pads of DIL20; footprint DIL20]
Designator prefix IC; gates A=74533 P=PWRN

## 74ALS533N  [DIL20]
1  A:OC  in
2  A:1Q  hiz
3  A:1D  in
4  A:2D  in
5  A:2Q  hiz
6  A:3Q  hiz
7  A:3D  in
8  A:4D  in
9  A:4Q  hiz
10  P:GND  pwr
11  A:C  in
12  A:5Q  hiz
13  A:5D  in
14  A:6D  in
15  A:6Q  hiz
16  A:7Q  hiz
17  A:7D  in
18  A:8D  in
19  A:8Q  hiz
20  P:VCC  pwr

## Footprint DIL20 (pad centres in mm)
Dual In Line Package
drill 0.813 long: 1 -11.43,-3.81; 2 -8.89,-3.81; 3 -6.35,-3.81; 4 -3.81,-3.81; 5 -1.27,-3.81; 6 1.27,-3.81; 7 3.81,-3.81; 8 6.35,-3.81; 9 8.89,-3.81; 10 11.43,-3.81; 11 11.43,3.81; 12 8.89,3.81; 13 6.35,3.81; 14 3.81,3.81; 15 1.27,3.81; 16 -1.27,3.81; 17 -3.81,3.81; 18 -6.35,3.81; 19 -8.89,3.81; 20 -11.43,3.81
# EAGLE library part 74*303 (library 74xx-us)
Octal devide by 2 CIRCUITS/CLOCK DRIVER

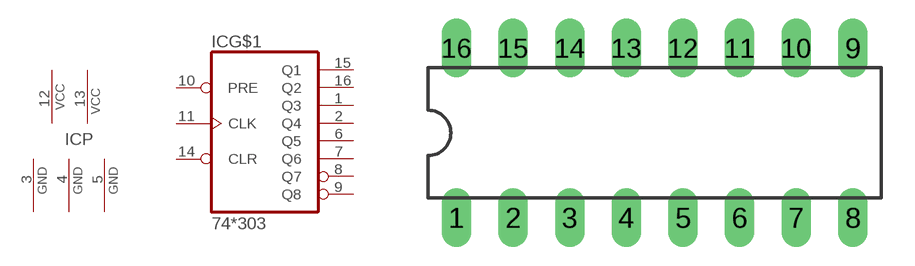
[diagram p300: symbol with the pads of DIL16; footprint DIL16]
Designator prefix IC; gates G$1=74303 P=2PWR3GND

## 74303N  [DIL16]
1  G$1:Q3  out
2  G$1:Q4  out
3  P:GND  pwr
4  P:GND  pwr
5  P:GND  pwr
6  G$1:Q5  out
7  G$1:Q6  out
8  G$1:Q7  out
9  G$1:Q8  out
10  G$1:PRE  in
11  G$1:CLK  in
12  P:VCC  pwr
13  P:VCC  pwr
14  G$1:CLR  in
15  G$1:Q1  out
16  G$1:Q2  out

## Footprint DIL16 (pad centres in mm)
Dual In Line Package
drill 0.813 long: 1 -8.89,-3.81; 2 -6.35,-3.81; 3 -3.81,-3.81; 4 -1.27,-3.81; 5 1.27,-3.81; 6 3.81,-3.81; 7 6.35,-3.81; 8 8.89,-3.81; 9 8.89,3.81; 10 6.35,3.81; 11 3.81,3.81; 12 1.27,3.81; 13 -1.27,3.81; 14 -3.81,3.81; 15 -6.35,3.81; 16 -8.89,3.81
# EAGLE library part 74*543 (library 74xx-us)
8-bit bidirectional BUS DRIVER, latch

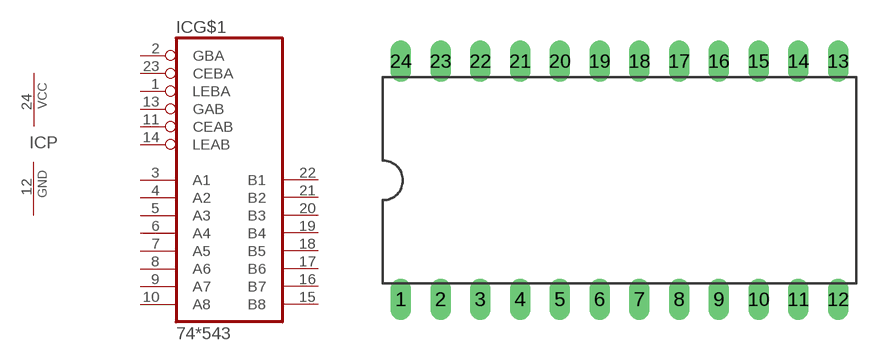
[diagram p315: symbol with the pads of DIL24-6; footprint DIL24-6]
Designator prefix IC; gates G$1=74543 P=PWRN

## 74HCT543N  [DIL24-6]
1  G$1:LEBA  in
2  G$1:GBA  in
3  G$1:A1
4  G$1:A2
5  G$1:A3
6  G$1:A4
7  G$1:A5
8  G$1:A6
9  G$1:A7
10  G$1:A8
11  G$1:CEAB  in
12  P:GND  pwr
13  G$1:GAB  in
14  G$1:LEAB  in
15  G$1:B8  hiz
16  G$1:B7  hiz
17  G$1:B6  hiz
18  G$1:B5  hiz
19  G$1:B4  hiz
20  G$1:B3  hiz
21  G$1:B2  hiz
22  G$1:B1  hiz
23  G$1:CEBA  in
24  P:VCC  pwr

## Footprint DIL24-6 (pad centres in mm)
Dual In Line Package 0.6 inch
drill 0.813 long: 1 -13.97,-7.62; 2 -11.43,-7.62; 3 -8.89,-7.62; 4 -6.35,-7.62; 5 -3.81,-7.62; 6 -1.27,-7.62; 7 1.27,-7.62; 8 3.81,-7.62; 9 6.35,-7.62; 10 8.89,-7.62; 11 11.43,-7.62; 12 13.97,-7.62; 13 13.97,7.62; 14 11.43,7.62; 15 8.89,7.62; 16 6.35,7.62; 17 3.81,7.62; 18 1.27,7.62; 19 -1.27,7.62; 20 -3.81,7.62; 21 -6.35,7.62; 22 -8.89,7.62; 23 -11.43,7.62; 24 -13.97,7.62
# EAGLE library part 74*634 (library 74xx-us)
32-bit EDAC error detection and correction

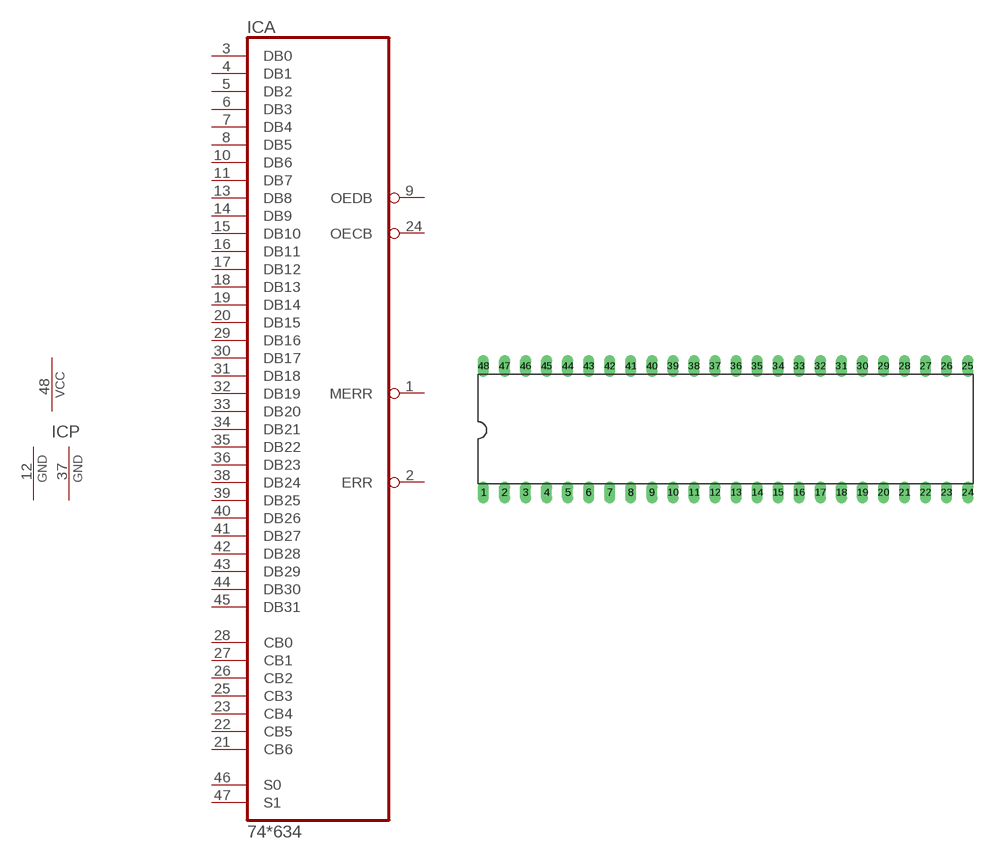
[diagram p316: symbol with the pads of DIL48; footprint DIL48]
Designator prefix IC; gates A=74634 P=PWR2GND

## 74ALS634JD  [DIL48]
1  A:MERR  out
2  A:ERR  out
3  A:DB0
4  A:DB1
5  A:DB2
6  A:DB3
7  A:DB4
8  A:DB5
9  A:OEDB  hiz
10  A:DB6
11  A:DB7
12  P:GND  pwr
13  A:DB8
14  A:DB9
15  A:DB10
16  A:DB11
17  A:DB12
18  A:DB13
19  A:DB14
20  A:DB15
21  A:CB6
22  A:CB5
23  A:CB4
24  A:OECB  hiz
25  A:CB3
26  A:CB2
27  A:CB1
28  A:CB0
29  A:DB16
30  A:DB17
31  A:DB18
32  A:DB19
33  A:DB20
34  A:DB21
35  A:DB22
36  A:DB23
37  P:GND  pwr
38  A:DB24
39  A:DB25
40  A:DB26
41  A:DB27
42  A:DB28
43  A:DB29
44  A:DB30
45  A:DB31
46  A:S0  in
47  A:S1  in
48  P:VCC  pwr

## Footprint DIL48 (pad centres in mm)
Dual In Line Package
drill 0.813 long: 1 -29.21,-7.62; 2 -26.67,-7.62; 3 -24.13,-7.62; 4 -21.59,-7.62; 5 -19.05,-7.62; 6 -16.51,-7.62; 7 -13.97,-7.62; 8 -11.43,-7.62; 9 -8.89,-7.62; 10 -6.35,-7.62; 11 -3.81,-7.62; 12 -1.27,-7.62; 13 1.27,-7.62; 14 3.81,-7.62; 15 6.35,-7.62; 16 8.89,-7.62; 17 11.43,-7.62; 18 13.97,-7.62; 19 16.51,-7.62; 20 19.05,-7.62; 21 21.59,-7.62; 22 24.13,-7.62; 23 26.67,-7.62; 24 29.21,-7.62; 25 29.21,7.62; 26 26.67,7.62; 27 24.13,7.62; 28 21.59,7.62; 29 19.05,7.62; 30 16.51,7.62; 31 13.97,7.62; 32 11.43,7.62; 33 8.89,7.62; 34 6.35,7.62; 35 3.81,7.62; 36 1.27,7.62; 37 -1.27,7.62; 38 -3.81,7.62; 39 -6.35,7.62; 40 -8.89,7.62; 41 -11.43,7.62; 42 -13.97,7.62; 43 -16.51,7.62; 44 -19.05,7.62; 45 -21.59,7.62; 46 -24.13,7.62; 47 -26.67,7.62; 48 -29.21,7.62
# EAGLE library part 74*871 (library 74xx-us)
2 x 16 REGISTER, 4 bit each

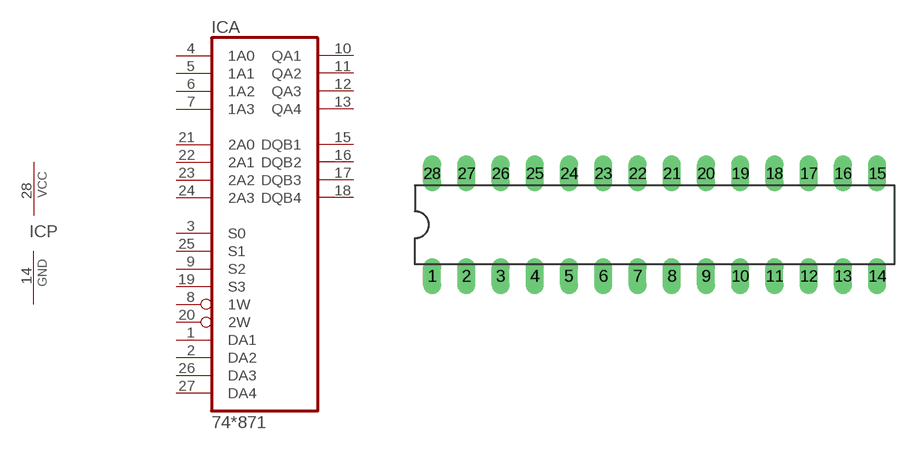
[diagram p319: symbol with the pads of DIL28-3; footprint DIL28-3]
Designator prefix IC; gates A=74871 P=PWRN

## 74AS871N  [DIL28-3]
1  A:DA1  in
2  A:DA2  in
3  A:S0  in
4  A:1A0  in
5  A:1A1  in
6  A:1A2  in
7  A:1A3  in
8  A:1W  in
9  A:S2  in
10  A:QA1  out
11  A:QA2  out
12  A:QA3  out
13  A:QA4  out
14  P:GND  pwr
15  A:DQB1
16  A:DQB2
17  A:DQB3
18  A:DQB4
19  A:S3  in
20  A:2W  in
21  A:2A0  in
22  A:2A1  in
23  A:2A2  in
24  A:2A3  in
25  A:S1  in
26  A:DA3  in
27  A:DA4  in
28  P:VCC  pwr

## Footprint DIL28-3 (pad centres in mm)
Dual In Line Package Small
drill 0.813 long: 1 -16.51,-3.81; 2 -13.97,-3.81; 3 -11.43,-3.81; 4 -8.89,-3.81; 5 -6.35,-3.81; 6 -3.81,-3.81; 7 -1.27,-3.81; 8 1.27,-3.81; 9 3.81,-3.81; 10 6.35,-3.81; 11 8.89,-3.81; 12 11.43,-3.81; 13 13.97,-3.81; 14 16.51,-3.81; 15 16.51,3.81; 16 13.97,3.81; 17 11.43,3.81; 18 8.89,3.81; 19 6.35,3.81; 20 3.81,3.81; 21 1.27,3.81; 22 -1.27,3.81; 23 -3.81,3.81; 24 -6.35,3.81; 25 -8.89,3.81; 26 -11.43,3.81; 27 -13.97,3.81; 28 -16.51,3.81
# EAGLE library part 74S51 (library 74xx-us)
AND OR INVERTER gates/for LS-type see 74*51

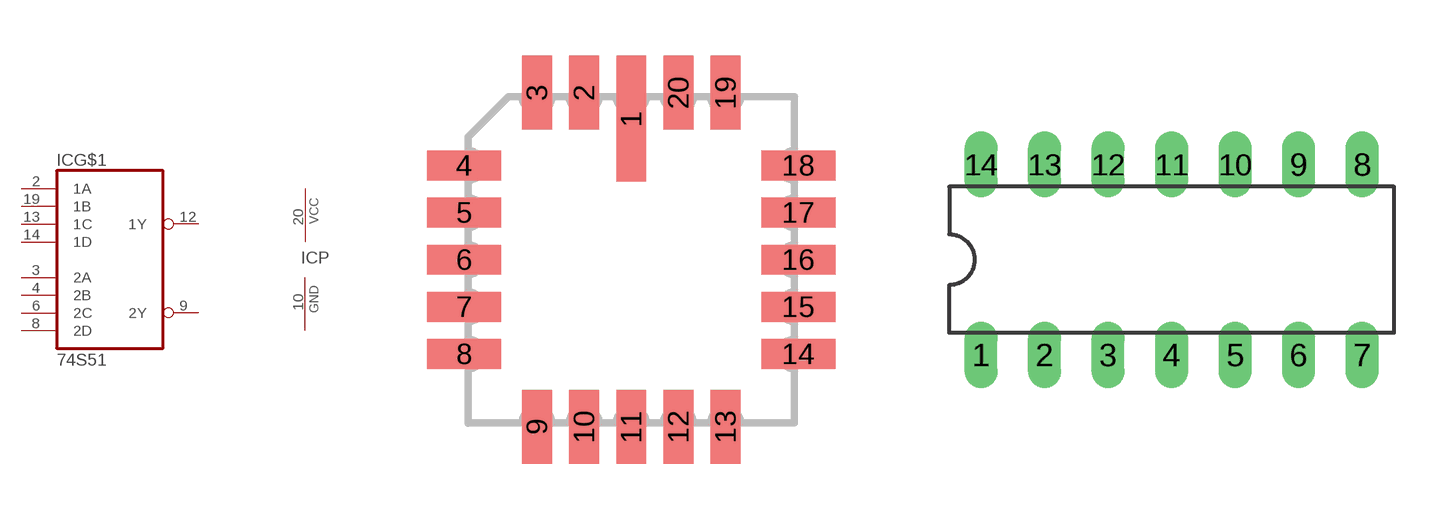
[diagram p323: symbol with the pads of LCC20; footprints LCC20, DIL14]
Designator prefix IC; gates P=PWRN G$1=74S51

## 74S51FK  [LCC20]
2  G$1:1A  in
3  G$1:2A  in
4  G$1:2B  in
6  G$1:2C  in
8  G$1:2D  in
9  G$1:2Y  out
10  P:GND  pwr
12  G$1:1Y  out
13  G$1:1C  in
14  G$1:1D  in
19  G$1:1B  in
20  P:VCC  pwr

## 74S51N  [DIL14]
1  G$1:1A  in
2  G$1:2A  in
3  G$1:2B  in
4  G$1:2C  in
5  G$1:2D  in
6  G$1:2Y  out
7  P:GND  pwr
8  G$1:1Y  out
9  G$1:1C  in
10  G$1:1D  in
13  G$1:1B  in
14  P:VCC  pwr

## 74S51D  [SO14]
Pads as for DIL14

## Footprint LCC20 (pad centres in mm)
Leadless Chip Carrier Ceramic Package
smd 0.8 x 3.4: 1 0,3.8
smd 0.8 x 2: 2 -1.27,4.5; 3 -2.54,4.5; 9 -2.54,-4.5; 10 -1.27,-4.5; 11 0,-4.5; 12 1.27,-4.5; 13 2.54,-4.5; 19 2.54,4.5; 20 1.27,4.5
smd 2 x 0.8: 4 -4.5,2.54; 5 -4.5,1.27; 6 -4.5,0; 7 -4.5,-1.27; 8 -4.5,-2.54; 14 4.5,-2.54; 15 4.5,-1.27; 16 4.5,0; 17 4.5,1.27; 18 4.5,2.54

## Footprint DIL14 (pad centres in mm)
Dual In Line Package
drill 0.813 long: 1 -7.62,-3.81; 2 -5.08,-3.81; 3 -2.54,-3.81; 4 0,-3.81; 5 2.54,-3.81; 6 5.08,-3.81; 7 7.62,-3.81; 8 7.62,3.81; 9 5.08,3.81; 10 2.54,3.81; 11 0,3.81; 12 -2.54,3.81; 13 -5.08,3.81; 14 -7.62,3.81

## Footprint SO14 (pad centres in mm)
Small Outline package 150 mil
smd 0.66 x 2.032: 1 -3.81,-3.073; 2 -2.54,-3.073; 3 -1.27,-3.073; 4 0,-3.073; 5 1.27,-3.073; 6 2.54,-3.073; 7 3.81,-3.073; 8 3.81,3.073; 9 2.54,3.073; 10 1.27,3.073; 11 0,3.073; 12 -1.27,3.073; 13 -2.54,3.073; 14 -3.81,3.073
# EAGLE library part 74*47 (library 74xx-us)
BCD to seven segment DECODER/DRIVER Source: http://www.ee.washington.edu/stores/DataSheets/74ls/74ls47.pdf

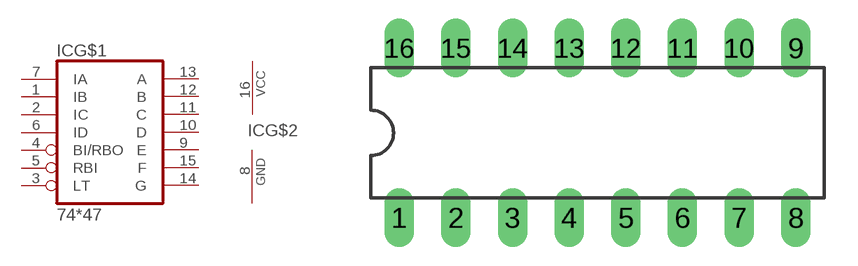
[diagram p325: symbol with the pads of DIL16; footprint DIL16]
Designator prefix IC; gates G$2=PWRN G$1=7447

## 74LS47N  [DIL16]
1  G$1:IB  in
2  G$1:IC  in
3  G$1:LT  in
4  G$1:BI/RBO  in
5  G$1:RBI  in
6  G$1:ID  in
7  G$1:IA  in
8  G$2:GND  pwr
9  G$1:E  out
10  G$1:D  out
11  G$1:C  out
12  G$1:B  out
13  G$1:A  out
14  G$1:G  out
15  G$1:F  out
16  G$2:VCC  pwr

## Footprint DIL16 (pad centres in mm)
Dual In Line Package
drill 0.813 long: 1 -8.89,-3.81; 2 -6.35,-3.81; 3 -3.81,-3.81; 4 -1.27,-3.81; 5 1.27,-3.81; 6 3.81,-3.81; 7 6.35,-3.81; 8 8.89,-3.81; 9 8.89,3.81; 10 6.35,3.81; 11 3.81,3.81; 12 1.27,3.81; 13 -1.27,3.81; 14 -3.81,3.81; 15 -6.35,3.81; 16 -8.89,3.81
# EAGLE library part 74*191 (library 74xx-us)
Synchronous UP/DOWN COUNTER

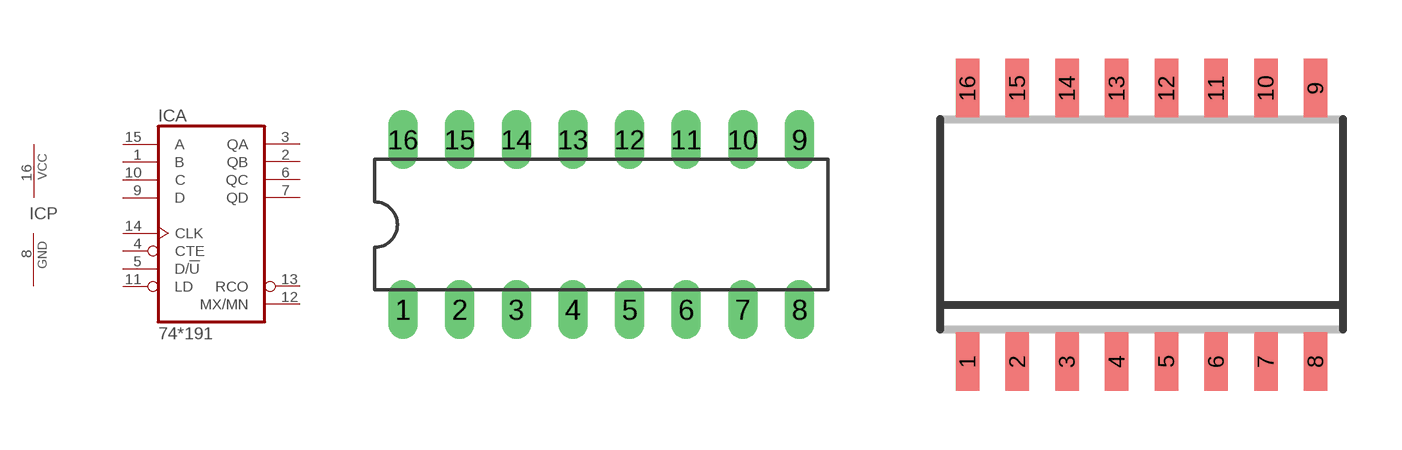
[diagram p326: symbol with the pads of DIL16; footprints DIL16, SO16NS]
Designator prefix IC; gates A=74190-1 P=PWRN-1

## 74191N, 74HC191N, 74HCT191N, 74LS191N  [DIL16]
1  A:B  in
2  A:QB  out
3  A:QA  out
4  A:CTE  in
5  A:D/!U  in
6  A:QC  out
7  A:QD  out
8  P:GND  pwr
9  A:D  in
10  A:C  in
11  A:LD  in
12  A:MX/MN  out
13  A:RCO  out
14  A:CLK  in
15  A:A  in
16  P:VCC  pwr

## 74HC191NS, 74HCT191NS  [SO16NS]
Pads as for DIL16

## 74HC191D, 74HCT191D  [SO16D]
Pads as for DIL16

## 74HC191PW, 74HCT191PW  [SO16PW]
Pads as for DIL16

## Footprint DIL16 (pad centres in mm)
Dual In Line Package
drill 0.813 long: 1 -8.89,-3.81; 2 -6.35,-3.81; 3 -3.81,-3.81; 4 -1.27,-3.81; 5 1.27,-3.81; 6 3.81,-3.81; 7 6.35,-3.81; 8 8.89,-3.81; 9 8.89,3.81; 10 6.35,3.81; 11 3.81,3.81; 12 1.27,3.81; 13 -1.27,3.81; 14 -3.81,3.81; 15 -6.35,3.81; 16 -8.89,3.81

## Footprint SO16NS (pad centres in mm)
Platic Small Outline NS R-PDSO-G16 Source: www.ti.com .. cd74hct191.pdf
smd 0.6 x 1.5: 1 -4.445,-3.49; 2 -3.175,-3.49; 3 -1.905,-3.49; 4 -0.635,-3.49; 5 0.635,-3.49; 6 1.905,-3.49; 7 3.175,-3.49; 8 4.445,-3.49; 9 4.445,3.49; 10 3.175,3.49; 11 1.905,3.49; 12 0.635,3.49; 13 -0.635,3.49; 14 -1.905,3.49; 15 -3.175,3.49; 16 -4.445,3.49

## Footprint SO16D (pad centres in mm)
Platic Small Outline D R-PDSO-G16 Source: www.ti.com .. cd74hct191.pdf
smd 0.6 x 1.4: 1 -4.445,-2.715; 2 -3.175,-2.715; 3 -1.905,-2.715; 4 -0.635,-2.715; 5 0.635,-2.715; 6 1.905,-2.715; 7 3.175,-2.715; 8 4.445,-2.715; 9 4.445,2.715; 10 3.175,2.715; 11 1.905,2.715; 12 0.635,2.715; 13 -0.635,2.715; 14 -1.905,2.715; 15 -3.175,2.715; 16 -4.445,2.715

## Footprint SO16PW (pad centres in mm)
SO16-pw R-PDSO-G Source: www.ti.com .. cd74hct191.pdf
smd 0.35 x 1.2: 1 -2.275,-2.825; 2 -1.625,-2.825; 3 -0.975,-2.825; 4 -0.325,-2.825; 5 0.325,-2.825; 6 0.975,-2.825; 7 1.625,-2.825; 8 2.275,-2.825; 9 2.275,2.825; 10 1.625,2.825; 11 0.975,2.825; 12 0.325,2.825; 13 -0.325,2.825; 14 -0.975,2.825; 15 -1.625,2.825; 16 -2.275,2.825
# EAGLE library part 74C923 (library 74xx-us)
20-Key Encoder Source: http://www.national.com/ds/MM/MM54C922.pdf#page=1

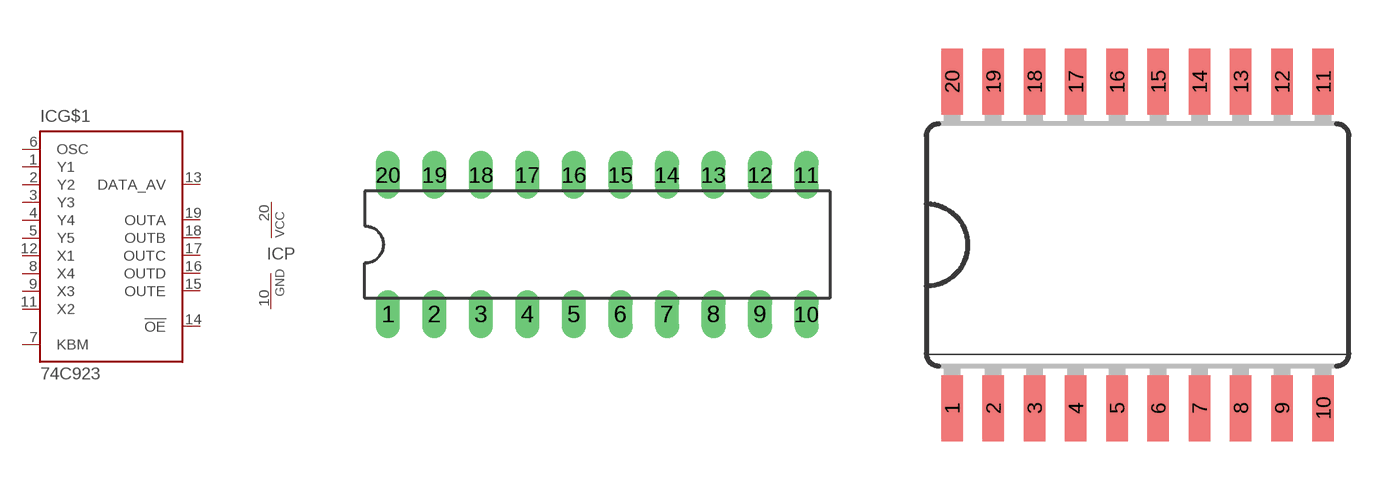
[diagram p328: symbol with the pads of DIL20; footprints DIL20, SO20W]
Designator prefix IC; gates G$1=74923 P=PWRN-2

## 74C923N  [DIL20]
1  G$1:Y1  in
2  G$1:Y2  in
3  G$1:Y3  in
4  G$1:Y4  in
5  G$1:Y5  in
6  G$1:OSC  in
7  G$1:KBM  in
8  G$1:X4  in
9  G$1:X3  in
10  P:GND  pwr
11  G$1:X2  in
12  G$1:X1  in
13  G$1:DATA_AV  out
14  G$1:!OE  in
15  G$1:OUTE  out
16  G$1:OUTD  out
17  G$1:OUTC  out
18  G$1:OUTB  out
19  G$1:OUTA  out
20  P:VCC  pwr

## 74C923M  [SO20W]
Pads as for DIL20

## Footprint DIL20 (pad centres in mm)
Dual In Line Package
drill 0.813 long: 1 -11.43,-3.81; 2 -8.89,-3.81; 3 -6.35,-3.81; 4 -3.81,-3.81; 5 -1.27,-3.81; 6 1.27,-3.81; 7 3.81,-3.81; 8 6.35,-3.81; 9 8.89,-3.81; 10 11.43,-3.81; 11 11.43,3.81; 12 8.89,3.81; 13 6.35,3.81; 14 3.81,3.81; 15 1.27,3.81; 16 -1.27,3.81; 17 -3.81,3.81; 18 -6.35,3.81; 19 -8.89,3.81; 20 -11.43,3.81

## Footprint SO20W (pad centres in mm)
Wide Small Outline package 300 mil
smd 0.66 x 2.032: 1 -5.715,-5.029; 2 -4.445,-5.029; 3 -3.175,-5.029; 4 -1.905,-5.029; 5 -0.635,-5.029; 6 0.635,-5.029; 7 1.905,-5.029; 8 3.175,-5.029; 9 4.445,-5.029; 10 5.715,-5.029; 11 5.715,5.029; 12 4.445,5.029; 13 3.175,5.029; 14 1.905,5.029; 15 0.635,5.029; 16 -0.635,5.029; 17 -1.905,5.029; 18 -3.175,5.029; 19 -4.445,5.029; 20 -5.715,5.029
